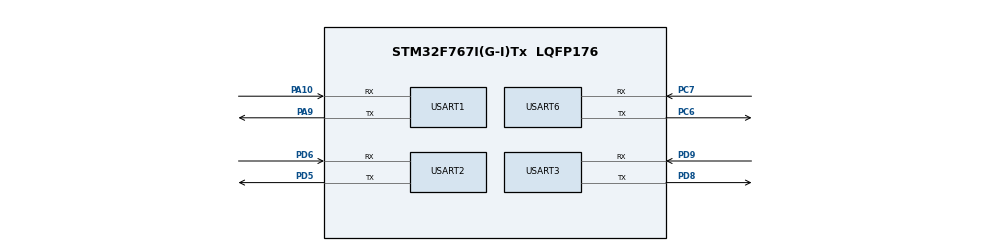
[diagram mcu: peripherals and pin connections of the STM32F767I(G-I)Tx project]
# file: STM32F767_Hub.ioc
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CORTEX_M7.default_mode_Activation=1
Mcu.Family=STM32F7
Mcu.Name=STM32F767I(G-I)Tx
Mcu.Package=LQFP176
NVIC.PriorityGroup=NVIC_PRIORITYGROUP_4
NVIC.USART2_IRQn=true\:5\:0\:true\:false\:true\:true\:true\:true
NVIC.USART3_IRQn=true\:5\:0\:true\:false\:true\:true\:true\:true
NVIC.USART6_IRQn=true\:5\:0\:true\:false\:true\:true\:true\:true
PA10.Mode=Asynchronous
PA10.Signal=USART1_RX
PA13.Mode=Serial_Wire
PA13.Signal=SYS_JTMS-SWDIO
PA14.Mode=Serial_Wire
PA14.Signal=SYS_JTCK-SWCLK
PA9.Mode=Asynchronous
PA9.Signal=USART1_TX
PC6.Mode=Asynchronous
PC6.Signal=USART6_TX
PC7.Mode=Asynchronous
PC7.Signal=USART6_RX
PD5.Mode=Asynchronous
PD5.Signal=USART2_TX
PD6.Mode=Asynchronous
PD6.Signal=USART2_RX
PD8.Mode=Asynchronous
PD8.Signal=USART3_TX
PD9.Mode=Asynchronous
PD9.Signal=USART3_RX
ProjectManager.HeapSize=0x200
ProjectManager.StackSize=0x400
ProjectManager.TargetToolchain=CMake
RCC.HSE_VALUE=25000000
RCC.HSI_VALUE=16000000
RCC.LSE_VALUE=32768
RCC.USBFreq_Value=96000000
RCC.VCOOutputFreq_Value=192000000
USART1.VirtualMode-Asynchronous=VM_ASYNC
USART2.VirtualMode-Asynchronous=VM_ASYNC
USART3.VirtualMode-Asynchronous=VM_ASYNC
USART6.VirtualMode-Asynchronous=VM_ASYNC
board=custom

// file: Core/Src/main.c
/* USER CODE BEGIN Header */
/**
  ******************************************************************************
  * @file           : main.c
  * @brief          : Main program body
  ******************************************************************************
  * @attention
  *
  * Copyright (c) 2026 STMicroelectronics.
  * All rights reserved.
  *
  * This software is licensed under terms that can be found in the LICENSE file
  * in the root directory of this software component.
  * If no LICENSE file comes with this software, it is provided AS-IS.
  *
  ******************************************************************************
  */
/* USER CODE END Header */
#include "main.h"
#include "usart.h"
#include "gpio.h"

/* USER CODE BEGIN Includes */
#include "app_hub.h"  // 引入调度器接口。
/* USER CODE END Includes */

void SystemClock_Config(void);
static void MPU_Config(void);

int main(void)
{

  /* MPU Configuration--------------------------------------------------------*/
  MPU_Config();

  /* MCU Configuration--------------------------------------------------------*/

  /* Reset of all peripherals, Initializes the Flash interface and the Systick. */
  HAL_Init();

  /* Configure the system clock */
  SystemClock_Config();

  /* Initialize all configured peripherals */
  MX_GPIO_Init();
  MX_USART1_UART_Init();
  MX_USART2_UART_Init();
  MX_USART3_UART_Init();
  MX_USART6_UART_Init();
  /* USER CODE BEGIN 2 */
  app_hub_init();  // 初始化三路从节点链路并启动接收中断。
  /* USER CODE END 2 */

  /* Infinite loop */
  while (1)
  {

    /* USER CODE BEGIN 3 */
    app_hub_run();  // 轮询调度三路从节点并转发应答至上位机。
  }
  /* USER CODE END 3 */
}

void SystemClock_Config(void)
{
  RCC_OscInitTypeDef RCC_OscInitStruct = {0};
  RCC_ClkInitTypeDef RCC_ClkInitStruct = {0};

  /** Configure the main internal regulator output voltage
  */
  __HAL_RCC_PWR_CLK_ENABLE();
  __HAL_PWR_VOLTAGESCALING_CONFIG(PWR_REGULATOR_VOLTAGE_SCALE1);

  /** Initializes the RCC Oscillators according to the specified parameters
  * in the RCC_OscInitTypeDef structure.
  */
  RCC_OscInitStruct.OscillatorType = RCC_OSCILLATORTYPE_HSE;
  RCC_OscInitStruct.HSEState = RCC_HSE_ON;
  RCC_OscInitStruct.PLL.PLLState = RCC_PLL_ON;
  RCC_OscInitStruct.PLL.PLLSource = RCC_PLLSOURCE_HSE;
  RCC_OscInitStruct.PLL.PLLM = 25;
  RCC_OscInitStruct.PLL.PLLN = 432;
  RCC_OscInitStruct.PLL.PLLP = RCC_PLLP_DIV2;
  RCC_OscInitStruct.PLL.PLLQ = 9;
  if (HAL_RCC_OscConfig(&RCC_OscInitStruct) != HAL_OK)
  {
    Error_Handler();
  }

  /** Activate the Over-Drive mode
  */
  if (HAL_PWREx_EnableOverDrive() != HAL_OK)
  {
    Error_Handler();
  }

  /** Initializes the CPU, AHB and APB buses clocks
  */
  RCC_ClkInitStruct.ClockType = RCC_CLOCKTYPE_HCLK|RCC_CLOCKTYPE_SYSCLK
                              |RCC_CLOCKTYPE_PCLK1|RCC_CLOCKTYPE_PCLK2;
  RCC_ClkInitStruct.SYSCLKSource = RCC_SYSCLKSOURCE_PLLCLK;
  RCC_ClkInitStruct.AHBCLKDivider = RCC_SYSCLK_DIV1;
  RCC_ClkInitStruct.APB1CLKDivider = RCC_HCLK_DIV4;
  RCC_ClkInitStruct.APB2CLKDivider = RCC_HCLK_DIV2;

  if (HAL_RCC_ClockConfig(&RCC_ClkInitStruct, FLASH_LATENCY_7) != HAL_OK)
  {
    Error_Handler();
  }
}

 /* MPU Configuration */

void MPU_Config(void)
{
  MPU_Region_InitTypeDef MPU_InitStruct = {0};

  /* Disables the MPU */
  HAL_MPU_Disable();

  /** Initializes and configures the Region and the memory to be protected
  */
  MPU_InitStruct.Enable = MPU_REGION_ENABLE;
  MPU_InitStruct.Number = MPU_REGION_NUMBER0;
  MPU_InitStruct.BaseAddress = 0x0;
  MPU_InitStruct.Size = MPU_REGION_SIZE_4GB;
  MPU_InitStruct.SubRegionDisable = 0x87;
  MPU_InitStruct.TypeExtField = MPU_TEX_LEVEL0;
  MPU_InitStruct.AccessPermission = MPU_REGION_NO_ACCESS;
  MPU_InitStruct.DisableExec = MPU_INSTRUCTION_ACCESS_DISABLE;
  MPU_InitStruct.IsShareable = MPU_ACCESS_SHAREABLE;
  MPU_InitStruct.IsCacheable = MPU_ACCESS_NOT_CACHEABLE;
  MPU_InitStruct.IsBufferable = MPU_ACCESS_NOT_BUFFERABLE;

  HAL_MPU_ConfigRegion(&MPU_InitStruct);
  /* Enables the MPU */
  HAL_MPU_Enable(MPU_PRIVILEGED_DEFAULT);

}

void Error_Handler(void)
{
  __disable_irq();
  while (1)
  {
  }
}
